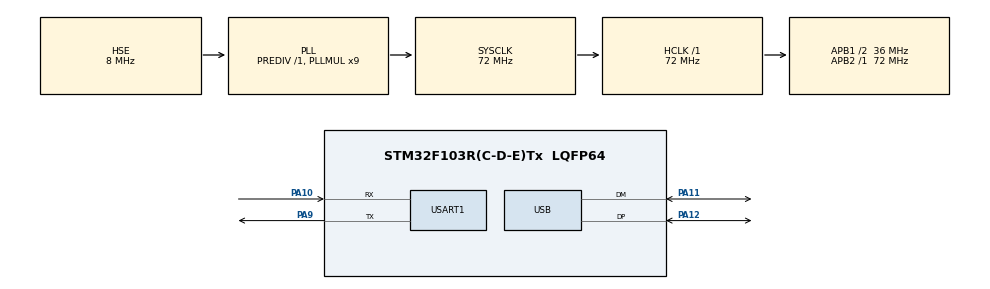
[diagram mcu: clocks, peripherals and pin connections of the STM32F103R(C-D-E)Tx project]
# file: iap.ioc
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Mcu.Family=STM32F1
Mcu.Name=STM32F103R(C-D-E)Tx
Mcu.Package=LQFP64
NVIC.PriorityGroup=NVIC_PRIORITYGROUP_4
NVIC.USART1_IRQn=true\:0\:0\:false\:false\:true
NVIC.USB_LP_CAN1_RX0_IRQn=true\:0\:0\:false\:false\:true
PA10.Mode=Asynchronous
PA10.Signal=USART1_RX
PA11.Mode=Device
PA11.Signal=USB_DM
PA12.Mode=Device
PA12.Signal=USB_DP
PA9.Mode=Asynchronous
PA9.Signal=USART1_TX
PD0-OSC_IN.Mode=HSE-External-Oscillator
PD0-OSC_IN.Signal=RCC_OSC_IN
PD1-OSC_OUT.Mode=HSE-External-Oscillator
PD1-OSC_OUT.Signal=RCC_OSC_OUT
ProjectManager.HeapSize=0x200
ProjectManager.StackSize=0x1000
ProjectManager.TargetToolchain=MDK-ARM V5
RCC.AHBFreq_Value=72000000
RCC.APB1CLKDivider=RCC_HCLK_DIV2
RCC.APB1Freq_Value=36000000
RCC.APB1TimFreq_Value=72000000
RCC.APB2Freq_Value=72000000
RCC.APB2TimFreq_Value=72000000
RCC.HCLKFreq_Value=72000000
RCC.PLLMUL=RCC_PLL_MUL9
RCC.SYSCLKFreq_VALUE=72000000
RCC.SYSCLKSource=RCC_SYSCLKSOURCE_PLLCLK
RCC.USBFreq_Value=48000000
RCC.USBPrescaler=RCC_USBCLKSOURCE_PLL_DIV1_5
USART1.VirtualMode=VM_ASYNC
USB_DEVICE.CLASS_NAME_FS=DFU
USB_DEVICE.VirtualMode=Dfu
USB_DEVICE.VirtualModeFS=Dfu_FS
VP_USB_DEVICE_VS_USB_DEVICE_DFU_FS.Mode=DFU_FS
board=iap

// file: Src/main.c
/**
  ******************************************************************************
  * File Name          : main.c
  * Description        : Main program body
  ******************************************************************************
  *
  * Copyright (c) 2017 STMicroelectronics International N.V.
  * All rights reserved.
  *
  * Redistribution and use in source and binary forms, with or without
  * modification, are permitted, provided that the following conditions are met:
  *
  * 1. Redistribution of source code must retain the above copyright notice,
  *    this list of conditions and the following disclaimer.
  * 2. Redistributions in binary form must reproduce the above copyright notice,
  *    this list of conditions and the following disclaimer in the documentation
  *    and/or other materials provided with the distribution.
  * 3. Neither the name of STMicroelectronics nor the names of other
  *    contributors to this software may be used to endorse or promote products
  *    derived from this software without specific written permission.
  * 4. This software, including modifications and/or derivative works of this
  *    software, must execute solely and exclusively on microcontroller or
  *    microprocessor devices manufactured by or for STMicroelectronics.
  * 5. Redistribution and use of this software other than as permitted under
  *    this license is void and will automatically terminate your rights under
  *    this license.
  *
  * THIS SOFTWARE IS PROVIDED BY STMICROELECTRONICS AND CONTRIBUTORS "AS IS"
  * AND ANY EXPRESS, IMPLIED OR STATUTORY WARRANTIES, INCLUDING, BUT NOT
  * LIMITED TO, THE IMPLIED WARRANTIES OF MERCHANTABILITY, FITNESS FOR A
  * PARTICULAR PURPOSE AND NON-INFRINGEMENT OF THIRD PARTY INTELLECTUAL PROPERTY
  * RIGHTS ARE DISCLAIMED TO THE FULLEST EXTENT PERMITTED BY LAW. IN NO EVENT
  * SHALL STMICROELECTRONICS OR CONTRIBUTORS BE LIABLE FOR ANY DIRECT, INDIRECT,
  * INCIDENTAL, SPECIAL, EXEMPLARY, OR CONSEQUENTIAL DAMAGES (INCLUDING, BUT NOT
  * LIMITED TO, PROCUREMENT OF SUBSTITUTE GOODS OR SERVICES; LOSS OF USE, DATA,
  * OR PROFITS; OR BUSINESS INTERRUPTION) HOWEVER CAUSED AND ON ANY THEORY OF
  * LIABILITY, WHETHER IN CONTRACT, STRICT LIABILITY, OR TORT (INCLUDING
  * NEGLIGENCE OR OTHERWISE) ARISING IN ANY WAY OUT OF THE USE OF THIS SOFTWARE,
  * EVEN IF ADVISED OF THE POSSIBILITY OF SUCH DAMAGE.
  *
  ******************************************************************************
  */
#include "main.h"
#include "stm32f1xx_hal.h"
#include "usb_device.h"

/* USER CODE BEGIN Includes */
#include "bsp_iap.h"
/* USER CODE END Includes */

UART_HandleTypeDef huart1;

/* USER CODE BEGIN PV */
/* Private variables ---------------------------------------------------------*/
uint8_t Rxdata;
/* USER CODE END PV */

void SystemClock_Config(void);
void Error_Handler(void);
static void MX_GPIO_Init(void);
static void MX_USART1_UART_Init(void);

/* USER CODE BEGIN PFP */
/* Private function prototypes -----------------------------------------------*/
//加入以下代码,支持printf函数,而不需要选择use MicroLIB
#if 1
#pragma import(__use_no_semihosting)
//标准库需要的支持函数
struct __FILE
{
	int handle;

};

FILE __stdout;
//定义_sys_exit()以避免使用半主机模式
void _sys_exit(int x)
{
	x = x;
}
//重定义fputc函数
int fputc(int ch, FILE *f)
{
	while((USART1->SR&0X40)==0){}//循环发送,直到发送完毕
  USART1->DR = (uint8_t) ch;
	return ch;
}
#endif
/* USER CODE END PFP */

/* USER CODE BEGIN 0 */
uint8_t scanKey1(void);
uint8_t scanKey0(void);
/* USER CODE END 0 */

int main(void)
{

  /* MCU Configuration----------------------------------------------------------*/

  /* Reset of all peripherals, Initializes the Flash interface and the Systick. */
  HAL_Init();

  /* Configure the system clock */
  SystemClock_Config();

  /* Initialize all configured peripherals */
  MX_GPIO_Init();
  MX_USART1_UART_Init();
  MX_USB_DEVICE_Init();

  /* USER CODE BEGIN 2 */
	printf("串口发送app程序\nkey1 rewrite app to flash\nkey0 turn to app\niap init!\n");
  /* USER CODE END 2 */

  /* Infinite loop */
  /* USER CODE BEGIN WHILE */
  while (1)
  {
		if(scanKey1()){
			IAP_Write_App_Bin(APP_START_ADDR, strAppBin .ucDataBuf, strAppBin .usLength );
			printf("load app!\n");
		}
		if(scanKey0()){
			printf("turn to app!\n");
			IAP_ExecuteApp(APP_START_ADDR);
		}
  /* USER CODE END WHILE */

  }

}

/** System Clock Configuration
*/
void SystemClock_Config(void)
{

  RCC_OscInitTypeDef RCC_OscInitStruct;
  RCC_ClkInitTypeDef RCC_ClkInitStruct;
  RCC_PeriphCLKInitTypeDef PeriphClkInit;

    /**Initializes the CPU, AHB and APB busses clocks
    */
  RCC_OscInitStruct.OscillatorType = RCC_OSCILLATORTYPE_HSE;
  RCC_OscInitStruct.HSEState = RCC_HSE_ON;
  RCC_OscInitStruct.HSEPredivValue = RCC_HSE_PREDIV_DIV1;
  RCC_OscInitStruct.PLL.PLLState = RCC_PLL_ON;
  RCC_OscInitStruct.PLL.PLLSource = RCC_PLLSOURCE_HSE;
  RCC_OscInitStruct.PLL.PLLMUL = RCC_PLL_MUL9;
  if (HAL_RCC_OscConfig(&RCC_OscInitStruct) != HAL_OK)
  {
    Error_Handler();
  }

    /**Initializes the CPU, AHB and APB busses clocks
    */
  RCC_ClkInitStruct.ClockType = RCC_CLOCKTYPE_HCLK|RCC_CLOCKTYPE_SYSCLK
                              |RCC_CLOCKTYPE_PCLK1|RCC_CLOCKTYPE_PCLK2;
  RCC_ClkInitStruct.SYSCLKSource = RCC_SYSCLKSOURCE_PLLCLK;
  RCC_ClkInitStruct.AHBCLKDivider = RCC_SYSCLK_DIV1;
  RCC_ClkInitStruct.APB1CLKDivider = RCC_HCLK_DIV2;
  RCC_ClkInitStruct.APB2CLKDivider = RCC_HCLK_DIV1;

  if (HAL_RCC_ClockConfig(&RCC_ClkInitStruct, FLASH_LATENCY_2) != HAL_OK)
  {
    Error_Handler();
  }

  PeriphClkInit.PeriphClockSelection = RCC_PERIPHCLK_USB;
  PeriphClkInit.UsbClockSelection = RCC_USBCLKSOURCE_PLL_DIV1_5;
  if (HAL_RCCEx_PeriphCLKConfig(&PeriphClkInit) != HAL_OK)
  {
    Error_Handler();
  }

    /**Configure the Systick interrupt time
    */
  HAL_SYSTICK_Config(HAL_RCC_GetHCLKFreq()/1000);

    /**Configure the Systick
    */
  HAL_SYSTICK_CLKSourceConfig(SYSTICK_CLKSOURCE_HCLK);

  /* SysTick_IRQn interrupt configuration */
  HAL_NVIC_SetPriority(SysTick_IRQn, 0, 0);
}

/* USART1 init function */
static void MX_USART1_UART_Init(void)
{

  huart1.Instance = USART1;
  huart1.Init.BaudRate = 115200;
  huart1.Init.WordLength = UART_WORDLENGTH_8B;
  huart1.Init.StopBits = UART_STOPBITS_1;
  huart1.Init.Parity = UART_PARITY_NONE;
  huart1.Init.Mode = UART_MODE_TX_RX;
  huart1.Init.HwFlowCtl = UART_HWCONTROL_NONE;
  huart1.Init.OverSampling = UART_OVERSAMPLING_16;
  if (HAL_UART_Init(&huart1) != HAL_OK)
  {
    Error_Handler();
  }
	HAL_UART_Receive_IT(&huart1,&Rxdata,1);
}
/**
  * 函数功能: 串口接收完成回调函数
  * 输入参数: 无
  * 返 回 值: 无
  * 说    明：无
  */
void HAL_UART_RxCpltCallback(UART_HandleTypeDef *UartHandle)
{
  if(strAppBin.usLength<APP_FLASH_LEN)
  {
		strAppBin.ucDataBuf[strAppBin.usLength++]=Rxdata;
  }
  HAL_UART_Receive_IT(&huart1,&Rxdata,1);
}
/*
funName	:scanKey1
input		:void
output	:void
describe:key 1 按键响应
remark	:
*/
uint8_t scanKey1(void){
	if(IsKey1Press){
		HAL_Delay(100);
		if(IsKey1Press){
			return 1;
		}
	}
	return 0;
}
/*
funName	:scanKey0
input		:void
output	:void
describe:key 0 按键响应
remark	:
*/
uint8_t scanKey0(void){
	if(IsKey0Press){
		HAL_Delay(100);
		if(IsKey0Press){
			return 1;
		}
	}
	return 0;
}
/** Configure pins as
        * Analog
        * Input
        * Output
        * EVENT_OUT
        * EXTI
*/
static void MX_GPIO_Init(void)
{
	GPIO_InitTypeDef GPIO_InitStruct;
  /* GPIO Ports Clock Enable */
  __HAL_RCC_GPIOD_CLK_ENABLE();
  __HAL_RCC_GPIOA_CLK_ENABLE();
	__HAL_RCC_GPIOC_CLK_ENABLE();
	/*Configure GPIO pin : KEY0_Pin */
  GPIO_InitStruct.Pin = GPIO_PIN_5;
  GPIO_InitStruct.Mode = GPIO_MODE_INPUT;
  GPIO_InitStruct.Pull = GPIO_PULLUP;
  HAL_GPIO_Init(GPIOC, &GPIO_InitStruct);
	/*Configure GPIO pin : KEY1_Pin */
  GPIO_InitStruct.Pin = GPIO_PIN_15;
  GPIO_InitStruct.Mode = GPIO_MODE_INPUT;
  GPIO_InitStruct.Pull = GPIO_PULLUP;//外设下拉GND
  HAL_GPIO_Init(GPIOA, &GPIO_InitStruct);

}

void Error_Handler(void)
{
  while(1)
  {
  }
}

/************************ (C) COPYRIGHT STMicroelectronics *****END OF FILE****/
